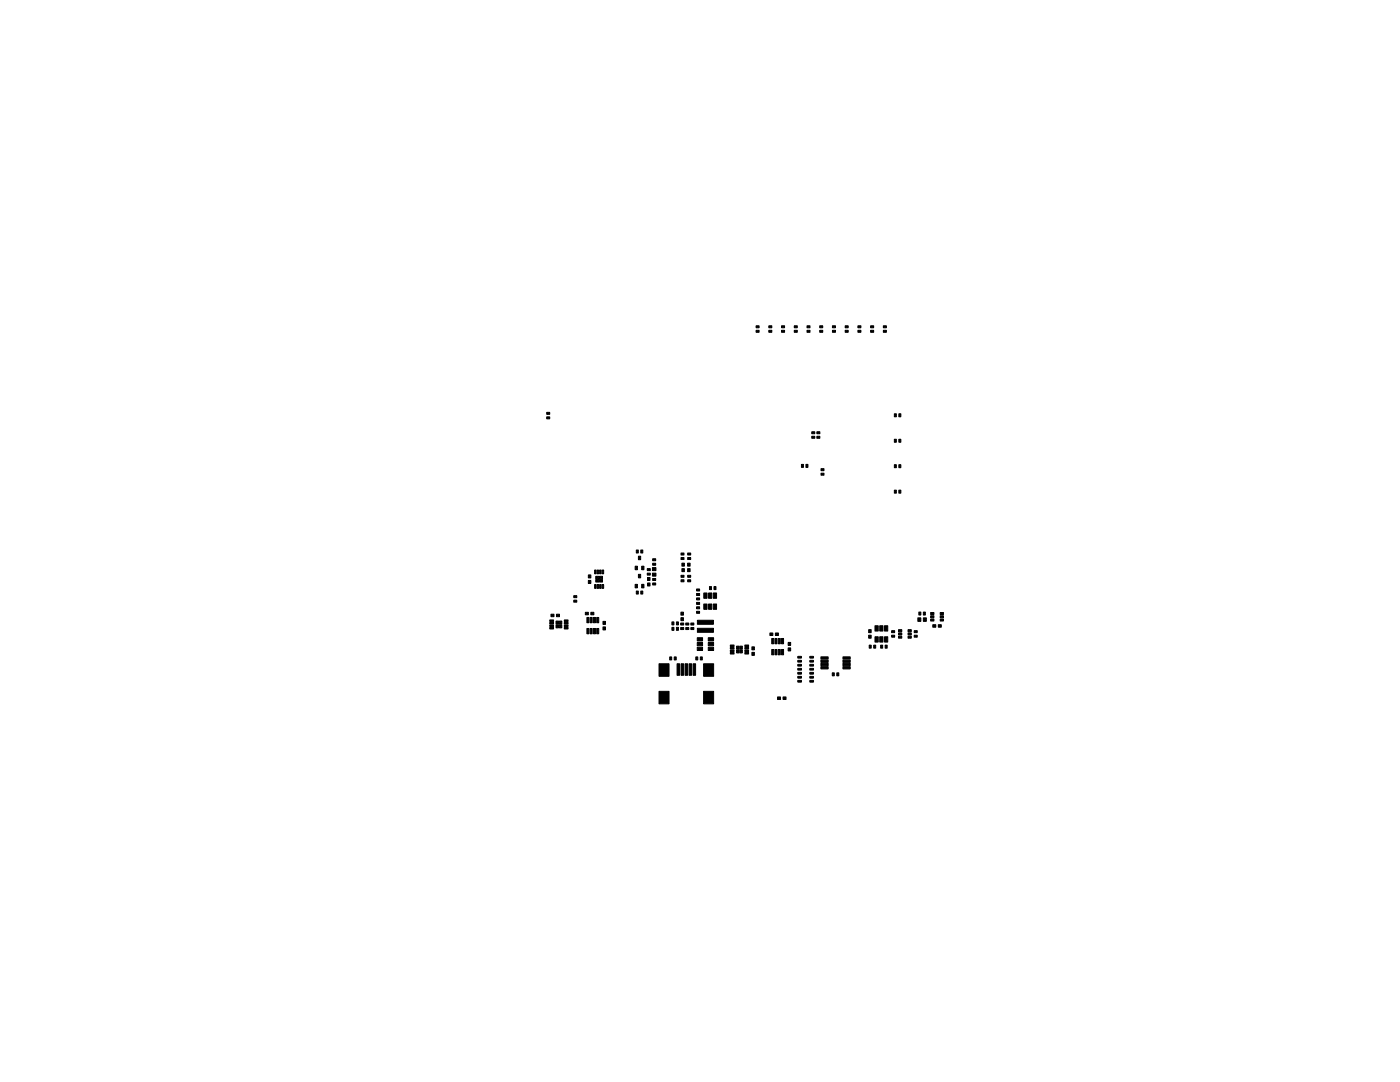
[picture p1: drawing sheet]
<svg xmlns="http://www.w3.org/2000/svg" width="279mm" height="216mm" viewBox="0 0 279 216" stroke-linecap="round" stroke-linejoin="round" font-family="sans-serif">
<g fill="#000" stroke="#000" stroke-width=".2">
<path d="M150.9 65.9h.6v.4h-.6zM150.9 65h.6v.4h-.6zM153.4 65.9h.6v.4h-.6zM153.4 65h.6v.4h-.6zM156 65.9h.6v.4h-.6zM156 65h.6v.4h-.6zM158.5 65.9h.6v.4h-.6zM158.5 65h.6v.4h-.6zM161.1 65.9h.6v.4h-.6zM161.1 65h.6v.4h-.6zM163.6 65.9h.6v.4h-.6zM163.6 65h.6v.4h-.6z"/>
<path d="M166.1 65.9h.6v.4h-.6zM166.1 65h.6v.4h-.6zM168.7 65.9h.6v.4h-.6zM168.7 65h.6v.4h-.6zM171.2 65h.6v.4h-.6zM171.2 65.9h.6v.4h-.6zM173.8 65.9h.6v.4h-.6zM173.8 65h.6v.4h-.6zM176.3 65.9h.6v.4h-.6zM176.3 65h.6v.4h-.6zM109.1 82.3h.6v.4h-.6zM109.1 83.2h.6v.4h-.6z"/>
<path d="M159.9 92.7h.4v.6h-.4zM160.8 92.7h.4v.6h-.4zM162 87.1h.6v.4h-.6zM162 86.2h.6v.4h-.6zM163 86.2h.6v.4h-.6zM163 87.1h.6v.4h-.6zM163.8 93.5h.6v.4h-.6zM163.8 94.4h.6v.4h-.6zM178.5 92.7h.4v.6h-.4zM178.5 97.8h.4v.6h-.4zM178.5 87.6h.4v.6h-.4zM178.5 82.6h.4v.6h-.4z"/>
<path d="M179.4 92.7h.4v.6h-.4zM179.4 97.8h.4v.6h-.4zM179.4 87.6h.4v.6h-.4zM179.4 82.6h.4v.6h-.4zM114.5 118.9h.6v.4h-.6zM117.4 114.7h.5v.6h-.5zM117.4 115.8h.5v.6h-.5zM118.7 116.6h.3v.8h-.3zM118.7 113.7h.3v.8h-.3zM118.9 115.6h.6v.5h-.6zM118.9 115h.6v.5h-.6zM119.2 116.6h.3v.8h-.3z"/>
<path d="M119.2 113.7h.3v.8h-.3zM119.6 115.6h.6v.5h-.6zM119.6 115h.6v.5h-.6zM119.7 116.6h.3v.8h-.3zM119.7 113.7h.3v.8h-.3zM120.2 116.6h.3v.8h-.3zM120.2 113.7h.3v.8h-.3zM127 109.7h.4v.6h-.4zM127 117.9h.4v.6h-.4zM126.8 113h.4v.7h-.4zM126.8 116.6h.4v.7h-.4zM127.4 111h.5v.7h-.5z"/>
<path d="M127.4 114.6h.5v.7h-.5zM127.9 109.7h.4v.6h-.4zM127.9 117.9h.4v.6h-.4zM128.1 113h.4v.7h-.4zM128.1 116.6h.4v.7h-.4zM129.2 116.3h.5v.6h-.5zM129.2 115.2h.5v.6h-.5zM129.2 113.5h.6v.4h-.6zM129.2 114.4h.6v.4h-.6zM130.2 114.4h.7v.6h-.7zM130.2 113.3h.7v.6h-.7zM130.3 112.4h.6v.4h-.6z"/>
<path d="M130.3 111.5h.6v.4h-.6zM130.3 116.3h.6v.4h-.6zM130.3 115.4h.6v.4h-.6zM135.9 111.2h.6v.4h-.6zM135.9 110.3h.6v.4h-.6zM135.9 114.8h.6v.4h-.6zM135.9 115.7h.6v.4h-.6zM136.1 112.4h.5v.6h-.5zM136.1 113.5h.5v.6h-.5zM137.2 113.5h.5v.6h-.5zM137.2 112.4h.5v.6h-.5zM137.2 111.2h.6v.4h-.6z"/>
<path d="M137.2 110.3h.6v.4h-.6zM137.2 114.8h.6v.4h-.6zM137.2 115.7h.6v.4h-.6zM139 117.5h.6v.4h-.6zM139 118.4h.6v.4h-.6zM139 119.3h.6v.4h-.6zM140.5 118.3h.6v1.1h-.6zM141.6 117h.4v.6h-.4zM141.4 118.3h.7v1.1h-.7zM142.5 117h.4v.6h-.4zM142.4 118.3h.6v1.1h-.6zM110 122.6h.6v.5h-.6z"/>
<path d="M109.7 125.2h.8v.3h-.8zM109.7 124.7h.8v.3h-.8zM109.7 124.2h.8v.3h-.8zM109.7 123.7h.8v.3h-.8zM111.1 122.6h.6v.5h-.6zM111 123.9h.5v.6h-.5zM111 124.7h.5v.6h-.5zM111.6 123.9h.5v.6h-.5zM111.6 124.7h.5v.6h-.5zM112.6 123.7h.8v.3h-.8zM112.6 124.2h.8v.3h-.8zM112.6 124.7h.8v.3h-.8z"/>
<path d="M112.6 125.2h.8v.3h-.8zM114.5 119.8h.6v.4h-.6zM116.8 122.2h.6v.5h-.6zM117.1 125.4h.4v1.1h-.4zM117.1 123.2h.4v1.1h-.4zM117.8 125.4h.4v1.1h-.4zM117.8 123.2h.4v1.1h-.4zM117.9 122.2h.6v.5h-.6zM118.4 125.4h.4v1.1h-.4zM118.4 123.2h.4v1.1h-.4zM119.1 125.4h.4v1.1h-.4zM119.1 123.2h.4v1.1h-.4z"/>
<path d="M120.3 125.1h.5v.6h-.5zM120.3 124h.5v.6h-.5zM131.5 132.4h2v2.5h-2zM133.7 131.1h.4v.6h-.4zM134.1 125.2h.4v.6h-.4zM134.1 124.1h.4v.6h-.4zM134.6 131.1h.4v.6h-.4zM135 125.2h.4v.6h-.4zM135 124.1h.4v.6h-.4zM135.1 132.4h.5v2.3h-.5zM135.8 125.2h.6v.4h-.6zM135.8 124.3h.6v.4h-.6z"/>
<path d="M135.9 122.2h.5v.6h-.5zM135.9 123.2h.5v.6h-.5zM135.9 132.4h.5v2.3h-.5zM136.9 125.2h.6v.4h-.6zM136.9 124.3h.6v.4h-.6zM136.7 132.4h.5v2.3h-.5zM137.9 124.3h.6v.4h-.6zM137.9 125.2h.6v.4h-.6zM137.5 132.4h.5v2.3h-.5zM138.3 132.4h.5v2.3h-.5zM138.9 131.1h.4v.6h-.4zM139.2 125.4h3.2v.8h-3.2z"/>
<path d="M139.2 123.8h3.2v.8h-3.2zM139 120.2h.6v.4h-.6zM139 121.1h.6v.4h-.6zM139 122h.6v.4h-.6zM139.8 131.1h.4v.6h-.4zM139.2 128.2h1v.6h-1zM139.2 127.2h1v.7h-1zM139.2 129.1h1v.7h-1zM140.5 120.5h.6v1.1h-.6zM141.4 120.5h.7v1.1h-.7zM141.3 129.1h1.1v.7h-1.1zM141.3 128.2h1.1v.6h-1.1z"/>
<path d="M141.3 127.2h1.1v.7h-1.1zM140.4 132.4h2v2.5h-2zM142.4 120.5h.6v1.1h-.6zM145.7 128.7h.8v.3h-.8zM145.7 129.2h.8v.3h-.8zM145.7 129.7h.8v.3h-.8zM145.7 130.2h.8v.3h-.8zM147 128.9h.5v.6h-.5zM147 129.7h.5v.6h-.5zM147.6 128.9h.5v.6h-.5zM147.6 129.7h.5v.6h-.5zM148.6 130.2h.8v.3h-.8z"/>
<path d="M148.6 129.7h.8v.3h-.8zM148.6 129.2h.8v.3h-.8zM148.6 128.7h.8v.3h-.8zM150.1 129.1h.5v.6h-.5zM150.1 130.2h.5v.6h-.5zM153.6 126.3h.6v.5h-.6zM154 129.6h.4v1.1h-.4zM154 127.4h.4v1.1h-.4zM154.7 129.6h.4v1.1h-.4zM154.7 127.4h.4v1.1h-.4zM154.7 126.3h.6v.5h-.6zM155.3 129.6h.4v1.1h-.4z"/>
<path d="M155.3 127.4h.4v1.1h-.4zM155.2 139.1h.6v.5h-.6zM156 129.6h.4v1.1h-.4zM156 127.4h.4v1.1h-.4zM156.3 139.1h.6v.5h-.6zM157.3 129.3h.5v.6h-.5zM157.3 128.2h.5v.6h-.5zM159.2 135.8h.7l.1 .3h-.7zM159.2 135h.7l.1 .3h-.7zM159.2 134.2h.7l.1 .3h-.7zM159.2 133.4h.7l.1 .3h-.7zM159.2 132.6h.7l.1 .3h-.7z"/>
<path d="M159.2 131.8h.7l.1 .3h-.7zM159.2 131h.7l.1 .3h-.7zM161.6 131h.7l.1 .3h-.7zM161.6 131.8h.7l.1 .3h-.7zM161.6 132.6h.7l.1 .3h-.7zM161.6 133.4h.7l.1 .3h-.7zM161.6 134.2h.7l.1 .3h-.7zM161.6 135h.7l.1 .3h-.7zM161.6 135.8h.7l.1 .3h-.7zM163.8 133h1.5v.5h-1.5zM163.8 132.4h1.5v.4h-1.5zM163.8 131.7h1.5v.5h-1.5z"/>
<path d="M163.8 131.1h1.5v.4h-1.5zM166.1 134.3h.4v.6h-.4zM167 134.3h.4v.6h-.4zM168.2 131.1h1.5v.4h-1.5zM168.2 131.7h1.5v.5h-1.5zM168.2 132.4h1.5v.4h-1.5zM168.2 133h1.5v.5h-1.5zM173.4 126.7h.5v.6h-.5zM173.4 125.6h.5v.6h-.5zM173.5 128.7h.4v.6h-.4zM174.4 128.7h.4v.6h-.4zM174.6 124.9h.7v1h-.7z"/>
<path d="M174.6 127.1h.7v1h-.7zM175.8 128.7h.4v.6h-.4zM175.6 124.9h.6v1h-.6zM175.6 127.1h.6v1h-.6zM176.7 128.7h.4v.6h-.4zM176.5 124.9h.7v1h-.7zM176.5 127.1h.7v1h-.7zM177.9 126.7h.6v.4h-.6zM177.9 125.8h.6v.4h-.6zM179.3 126.3h.7v.4h-.7zM179.3 125.6h.7v.4h-.7zM179.3 126.9h.7v.4h-.7z"/>
<path d="M181.2 126.9h.7v.4h-.7zM181.2 125.6h.7v.4h-.7zM181.2 126.3h.7v.4h-.7zM182.5 125.8h.6v.4h-.6zM182.5 126.7h.6v.4h-.6zM183.2 123.3h.6v.7h-.6zM183.4 122.1h.4v.6h-.4zM184.3 123.3h.6v.7h-.6zM184.3 122.1h.4v.6h-.4zM186.2 124.7h.6v.5h-.6zM185.7 122.2h.7v.4h-.7zM185.7 123.5h.7v.4h-.7z"/>
<path d="M185.7 122.9h.7v.4h-.7zM187.3 124.7h.6v.5h-.6zM187.6 122.9h.7v.4h-.7zM187.6 123.5h.7v.4h-.7zM187.6 122.2h.7v.4h-.7zM131.5 137.9h2v2.5h-2zM140.4 137.9h2v2.5h-2z"/>
</g>
</svg>
